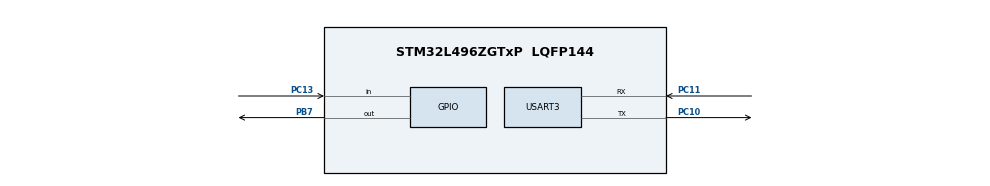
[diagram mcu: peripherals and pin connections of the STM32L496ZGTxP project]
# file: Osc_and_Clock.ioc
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Mcu.Family=STM32L4
Mcu.Name=STM32L496ZGTxP
Mcu.Package=LQFP144
NVIC.PriorityGroup=NVIC_PRIORITYGROUP_4
NVIC.USART3_IRQn=true\:0\:0\:false\:false\:true\:true\:true\:true
PB7.Signal=GPIO_Output
PC10.Mode=Asynchronous
PC10.Signal=USART3_TX
PC11.Mode=Asynchronous
PC11.Signal=USART3_RX
PC13.Signal=GPIO_Input
ProjectManager.HeapSize=0x200
ProjectManager.StackSize=0x400
ProjectManager.TargetToolchain=STM32CubeIDE
RCC.48MHZClocksFreq_Value=24000000
RCC.ADCFreq_Value=48000000
RCC.AHBCLKDivider=RCC_SYSCLK_DIV4
RCC.AHBFreq_Value=14200000
RCC.APB1CLKDivider=RCC_HCLK_DIV2
RCC.APB1Freq_Value=7100000
RCC.APB1TimFreq_Value=14200000
RCC.APB2Freq_Value=14200000
RCC.APB2TimFreq_Value=14200000
RCC.CortexFreq_Value=14200000
RCC.HCLKFreq_Value=14200000
RCC.HSE_VALUE=8000000
RCC.HSI48_VALUE=48000000
RCC.HSI_VALUE=16000000
RCC.MSIClockRange=RCC_MSIRANGE_9
RCC.MSI_VALUE=24000000
RCC.PLLM=5
RCC.PLLMUL=RCC_PLL_MUL9
RCC.PLLN=71
RCC.PLLR=RCC_PLLR_DIV6
RCC.PLLSAI1N=20
RCC.PRESCALERUSB=RCC_USBCLKSOURCE_PLL_DIV1_5
RCC.SYSCLKFreq_VALUE=56800000
RCC.SYSCLKSource=RCC_SYSCLKSOURCE_PLLCLK
RCC.SYSCLKSourceVirtual=RCC_SYSCLKSOURCE_PLLCLK
RCC.USBFreq_Value=48000000
RCC.VCOOutputFreq_Value=340800000
USART3.VirtualMode-Asynchronous=VM_ASYNC
board=NUCLEO-L496ZG-P

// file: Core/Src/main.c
/* USER CODE BEGIN Header */
/**
  ******************************************************************************
  * @file           : main.c
  * @brief          : Main program body
  ******************************************************************************
  * @attention
  *
  * Copyright (c) 2023 STMicroelectronics.
  * All rights reserved.
  *
  * This software is licensed under terms that can be found in the LICENSE file
  * in the root directory of this software component.
  * If no LICENSE file comes with this software, it is provided AS-IS.
  *
  ******************************************************************************
  */
/* USER CODE END Header */
#include "main.h"

/* USER CODE BEGIN Includes */
#include<string.h>
#include<stdio.h>
/* USER CODE END Includes */

UART_HandleTypeDef huart3;

void SystemClock_Config(void);
static void MX_GPIO_Init(void);
static void MX_USART3_UART_Init(void);

int main(void)
{
  /* USER CODE BEGIN 1 */
char buf[100];
  /* USER CODE END 1 */

  /* MCU Configuration--------------------------------------------------------*/

  /* Reset of all peripherals, Initializes the Flash interface and the Systick. */
  HAL_Init();

  /* Configure the system clock */
  SystemClock_Config();

  /* Initialize all configured peripherals */
  MX_GPIO_Init();
  MX_USART3_UART_Init();
  /* USER CODE BEGIN 2 */
  while(1){

while(! HAL_GPIO_ReadPin(GPIOC, GPIO_PIN_13));
HAL_Delay(200);
strcpy(buf,"Application is Running\n\r");
HAL_UART_Transmit(&huart3, (uint8_t*)buf, strlen(buf), HAL_MAX_DELAY);
HAL_GPIO_WritePin(GPIOB, GPIO_PIN_7, GPIO_PIN_SET);

sprintf(buf,"SYSCLOCK frequency : %ld\n\r",HAL_RCC_GetSysClockFreq());
HAL_UART_Transmit(&huart3, (uint8_t*)buf, strlen(buf), HAL_MAX_DELAY);

sprintf(buf,"HCLK frequency : %ld\n\r",HAL_RCC_GetHCLKFreq());
HAL_UART_Transmit(&huart3, (uint8_t*)buf, strlen(buf), HAL_MAX_DELAY);

sprintf(buf,"PCLOCK1 frequency : %ld\n\r",HAL_RCC_GetPCLK1Freq());
HAL_UART_Transmit(&huart3, (uint8_t*)buf, strlen(buf), HAL_MAX_DELAY);

sprintf(buf,"PCLOCK2 frequency : %ld\n\r",HAL_RCC_GetPCLK2Freq());
HAL_UART_Transmit(&huart3, (uint8_t*)buf, strlen(buf), HAL_MAX_DELAY);

  }
  /* USER CODE END 2 */

  /* Infinite loop */
  while (1)
  {

  }
}

void SystemClock_Config(void)
{
  RCC_OscInitTypeDef RCC_OscInitStruct = {0};
  RCC_ClkInitTypeDef RCC_ClkInitStruct = {0};

  memset(&RCC_OscInitStruct,0,sizeof(RCC_OscInitStruct));
//  RCC_OscInitStruct.OscillatorType=RCC_OSCILLATORTYPE_HSI;
//  RCC_OscInitStruct.HSIState=RCC_HSI_ON;

    RCC_OscInitStruct.OscillatorType = RCC_OSCILLATORTYPE_MSI;
    RCC_OscInitStruct.MSIState = RCC_MSI_ON;
    RCC_OscInitStruct.MSICalibrationValue = 0;
    RCC_OscInitStruct.MSIClockRange = RCC_MSIRANGE_9;
    RCC_OscInitStruct.PLL.PLLState = RCC_PLL_ON;
    RCC_OscInitStruct.PLL.PLLSource = RCC_PLLSOURCE_MSI;
    RCC_OscInitStruct.PLL.PLLM = 5;
    RCC_OscInitStruct.PLL.PLLN = 71;
    RCC_OscInitStruct.PLL.PLLP = RCC_PLLP_DIV2;
    RCC_OscInitStruct.PLL.PLLQ = RCC_PLLQ_DIV2;
    RCC_OscInitStruct.PLL.PLLR = RCC_PLLR_DIV6;

  if(HAL_RCC_OscConfig(&RCC_OscInitStruct) != HAL_OK ){
	  Error_Handler();
  }

  RCC_ClkInitStruct.ClockType= RCC_CLOCKTYPE_SYSCLK |RCC_CLOCKTYPE_HCLK |RCC_CLOCKTYPE_PCLK1
		  	  	  	  	  	  |RCC_CLOCKTYPE_PCLK2|RCC_CLOCKTYPE_SYSCLK;
  RCC_ClkInitStruct.SYSCLKSource =  RCC_SYSCLKSOURCE_PLLCLK;
  RCC_ClkInitStruct.AHBCLKDivider = RCC_SYSCLK_DIV2;
  RCC_ClkInitStruct.APB1CLKDivider = RCC_SYSCLK_DIV2;
  RCC_ClkInitStruct.APB2CLKDivider = RCC_SYSCLK_DIV2;

  if(HAL_RCC_ClockConfig(&RCC_ClkInitStruct,FLASH_LATENCY_0 ) != HAL_OK){
	  Error_Handler();
  }

  /*---------------------------------AFTER THIS LINE SYSCLK is SOURCED BY HSE-------------------------------------*/
  __HAL_RCC_HSI_DISABLE(); //this will save some current

  /* Lets Redo the SYSTICK CONFIGURATION */
  HAL_SYSTICK_Config(HAL_RCC_GetHCLKFreq()/1000);

  HAL_SYSTICK_CLKSourceConfig(SYSTICK_CLKSOURCE_HCLK);

//  /** Configure the main internal regulator output voltage
//  */
//  if (HAL_PWREx_ControlVoltageScaling(PWR_REGULATOR_VOLTAGE_SCALE1) != HAL_OK)
//  {
//    Error_Handler();
//  }
//
//  /** Initializes the RCC Oscillators according to the specified parameters
//  * in the RCC_OscInitTypeDef structure.
//  */
//  RCC_OscInitStruct.OscillatorType = RCC_OSCILLATORTYPE_MSI;
//  RCC_OscInitStruct.MSIState = RCC_MSI_ON;
//  RCC_OscInitStruct.MSICalibrationValue = 0;
//  RCC_OscInitStruct.MSIClockRange = RCC_MSIRANGE_9;
//  RCC_OscInitStruct.PLL.PLLState = RCC_PLL_ON;
//  RCC_OscInitStruct.PLL.PLLSource = RCC_PLLSOURCE_MSI;
//  RCC_OscInitStruct.PLL.PLLM = 5;
//  RCC_OscInitStruct.PLL.PLLN = 71;
//  RCC_OscInitStruct.PLL.PLLP = RCC_PLLP_DIV2;
//  RCC_OscInitStruct.PLL.PLLQ = RCC_PLLQ_DIV2;
//  RCC_OscInitStruct.PLL.PLLR = RCC_PLLR_DIV6;
//  if (HAL_RCC_OscConfig(&RCC_OscInitStruct) != HAL_OK)
//  {
//    Error_Handler();
//  }
//
//  /** Initializes the CPU, AHB and APB buses clocks
//  */
//  RCC_ClkInitStruct.ClockType = RCC_CLOCKTYPE_HCLK|RCC_CLOCKTYPE_SYSCLK
//                              |RCC_CLOCKTYPE_PCLK1|RCC_CLOCKTYPE_PCLK2;
//  RCC_ClkInitStruct.SYSCLKSource = RCC_SYSCLKSOURCE_PLLCLK;
//  RCC_ClkInitStruct.AHBCLKDivider = RCC_SYSCLK_DIV4;
//  RCC_ClkInitStruct.APB1CLKDivider = RCC_HCLK_DIV2;
//  RCC_ClkInitStruct.APB2CLKDivider = RCC_HCLK_DIV1;
//
//  if (HAL_RCC_ClockConfig(&RCC_ClkInitStruct, FLASH_LATENCY_0) != HAL_OK)
//  {
//    Error_Handler();
//  }
}

static void MX_USART3_UART_Init(void)
{

  huart3.Instance = USART3;
  huart3.Init.BaudRate = 115200;
  huart3.Init.WordLength = UART_WORDLENGTH_8B;
  huart3.Init.StopBits = UART_STOPBITS_1;
  huart3.Init.Parity = UART_PARITY_NONE;
  huart3.Init.Mode = UART_MODE_TX_RX;
  huart3.Init.HwFlowCtl = UART_HWCONTROL_NONE;
  huart3.Init.OverSampling = UART_OVERSAMPLING_16;
  huart3.Init.OneBitSampling = UART_ONE_BIT_SAMPLE_DISABLE;
  huart3.AdvancedInit.AdvFeatureInit = UART_ADVFEATURE_NO_INIT;
  if (HAL_UART_Init(&huart3) != HAL_OK)
  {
    Error_Handler();
  }

}

static void MX_GPIO_Init(void)
{
  GPIO_InitTypeDef GPIO_InitStruct = {0};

  /* GPIO Ports Clock Enable */
  __HAL_RCC_GPIOC_CLK_ENABLE();
  __HAL_RCC_GPIOB_CLK_ENABLE();

  /*Configure GPIO pin Output Level */
  HAL_GPIO_WritePin(GPIOB, GPIO_PIN_7, GPIO_PIN_RESET);

  /*Configure GPIO pin : PC13 */
  GPIO_InitStruct.Pin = GPIO_PIN_13;
  GPIO_InitStruct.Mode = GPIO_MODE_INPUT;
  GPIO_InitStruct.Pull = GPIO_NOPULL;
  HAL_GPIO_Init(GPIOC, &GPIO_InitStruct);

  /*Configure GPIO pin : PB7 */
  GPIO_InitStruct.Pin = GPIO_PIN_7;
  GPIO_InitStruct.Mode = GPIO_MODE_OUTPUT_PP;
  GPIO_InitStruct.Pull = GPIO_NOPULL;
  GPIO_InitStruct.Speed = GPIO_SPEED_FREQ_LOW;
  HAL_GPIO_Init(GPIOB, &GPIO_InitStruct);

}

void Error_Handler(void)
{
  __disable_irq();
  while (1)
  {
  }
}
